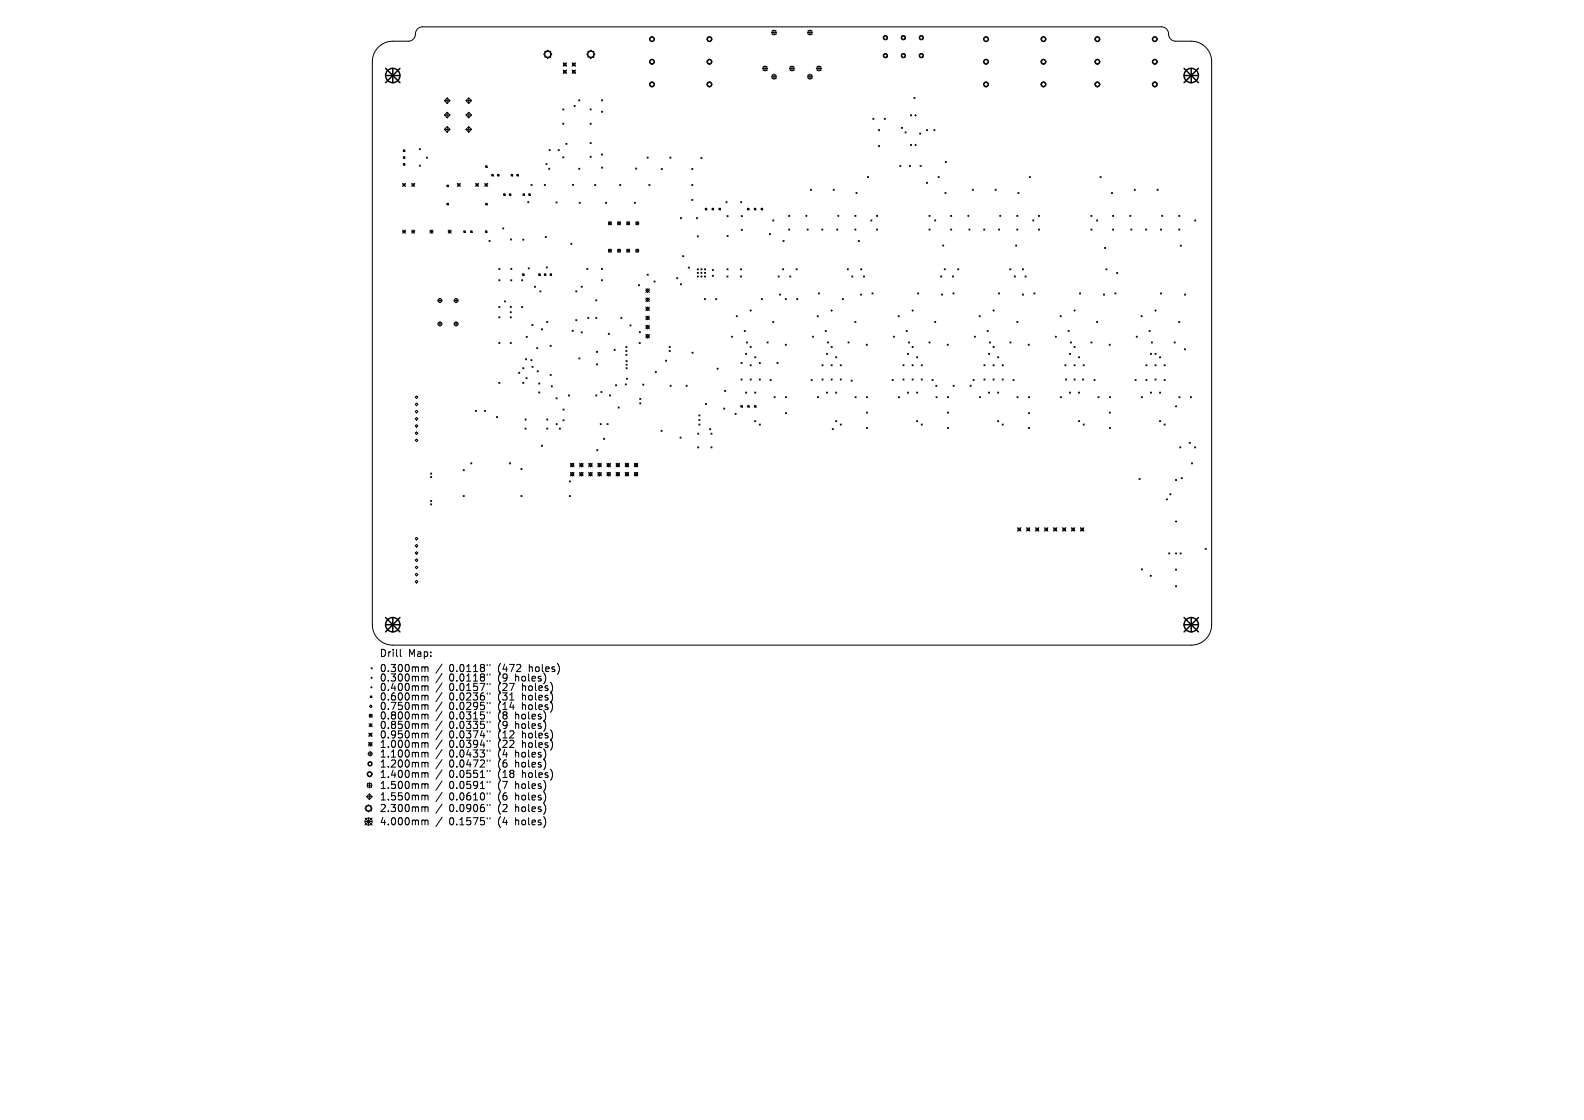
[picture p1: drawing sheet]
<svg xmlns="http://www.w3.org/2000/svg" width="297mm" height="210mm" viewBox="0 0 297 210" stroke-linecap="round" stroke-linejoin="round" font-family="sans-serif">
<defs><g id="words">
<g font-size="1.9">
<text x="71.1" y="123.4">Drill</text>
<text x="76.5" y="123.4">Map:</text>
<text x="71.1" y="126.2">0.300mm</text>
<text x="71.1" y="128">0.300mm</text>
<text x="71.1" y="129.7">0.400mm</text>
<text x="71.1" y="131.5">0.600mm</text>
<text x="84.2" y="126.2">0.0118&quot;</text>
<text x="84.2" y="128">0.0118&quot;</text>
<text x="84.2" y="129.7">0.0157&quot;</text>
<text x="84.2" y="131.5">0.0236&quot;</text>
<text x="93.5" y="126.2">(472</text>
<text x="93.5" y="128">(9</text>
<text x="93.5" y="129.7">(27</text>
<text x="93.5" y="131.5">(31</text>
<text x="96.8" y="128">holes)</text>
<text x="98.1" y="129.7">holes)</text>
<text x="98.1" y="131.5">holes)</text>
<text x="99.4" y="126.2">holes)</text>
<text x="71.1" y="133.3">0.750mm</text>
<text x="71.1" y="135.1">0.800mm</text>
<text x="71.1" y="136.9">0.850mm</text>
<text x="84.2" y="133.3">0.0295&quot;</text>
<text x="84.2" y="135.1">0.0315&quot;</text>
<text x="84.2" y="136.9">0.0335&quot;</text>
<text x="93.5" y="133.3">(14</text>
<text x="93.5" y="135.1">(8</text>
<text x="93.5" y="136.9">(9</text>
<text x="96.8" y="135.1">holes)</text>
<text x="96.8" y="136.9">holes)</text>
<text x="98.1" y="133.3">holes)</text>
<text x="71.1" y="138.6">0.950mm</text>
<text x="71.1" y="140.4">1.000mm</text>
<text x="71.1" y="142.2">1.100mm</text>
<text x="84.2" y="138.6">0.0374&quot;</text>
<text x="84.2" y="140.4">0.0394&quot;</text>
<text x="84.2" y="142.2">0.0433&quot;</text>
<text x="93.5" y="138.6">(12</text>
<text x="93.5" y="140.4">(22</text>
<text x="93.5" y="142.2">(4</text>
<text x="96.8" y="142.2">holes)</text>
<text x="98.1" y="138.6">holes)</text>
<text x="98.1" y="140.4">holes)</text>
<text x="71.1" y="144.1">1.200mm</text>
<text x="71.1" y="146">1.400mm</text>
<text x="71.1" y="148.1">1.500mm</text>
<text x="84.2" y="144.1">0.0472&quot;</text>
<text x="84.2" y="146">0.0551&quot;</text>
<text x="84.2" y="148.1">0.0591&quot;</text>
<text x="93.5" y="144.1">(6</text>
<text x="93.5" y="146">(18</text>
<text x="93.5" y="148.1">(7</text>
<text x="96.8" y="144.1">holes)</text>
<text x="96.8" y="148.1">holes)</text>
<text x="98.1" y="146">holes)</text>
<text x="71.1" y="150.3">1.550mm</text>
<text x="71.1" y="152.4">2.300mm</text>
<text x="71.1" y="154.9">4.000mm</text>
<text x="84.2" y="150.3">0.0610&quot;</text>
<text x="84.2" y="152.4">0.0906&quot;</text>
<text x="84.2" y="154.9">0.1575&quot;</text>
<text x="93.5" y="150.3">(6</text>
<text x="93.5" y="152.4">(2</text>
<text x="93.5" y="154.9">(4</text>
<text x="96.8" y="150.3">holes)</text>
<text x="96.8" y="152.4">holes)</text>
<text x="96.8" y="154.9">holes)</text>
</g>
</g></defs>
<g fill="none" stroke="#000" stroke-width=".19">
<path d="M70.9 8.8a3.8 3.8 0 0 1 2.7-1.1h2.9a1.48 1.48 0 0 0 1.4-1.7l.5-.7 .8-.3h138.6a1.47 1.47 0 0 1 1.4 1.7l.3 .6 .6 .4h3.3a3.8 3.8 0 0 1 3.8 3.9v105.5a3.8 3.8 0 0 1-3.8 3.9h-149.8a3.8 3.8 0 0 1-3.8-3.9v-105.5a3.8 3.8 0 0 1 1.1-2.8zM83.3 18.9l.5-.5 .6 .5-.6 .5zM83.3 18.9h1.1M83.8 18.4v1M87.4 18.9l.5-.5 .5 .5-.5 .5zM87.4 18.9h1M87.9 18.4v1M102.2 9.6h1.1v1.1h-1.1zM102.7 9.4l.8 .8-.8 .7-.8-.7zM105.6 11.8l.6 .6M105.6 13.1l.6 .7M105.7 11.9h.4v.4h-.4z"/>
<path d="M105.7 13.2h.4v.5h-.4zM106.2 11.8l-.6 .6M106.2 13.1l-.6 .7M107.3 11.8l.6 .6M107.3 13.1l.6 .7M107.4 11.9h.4v.4h-.4zM107.4 13.2h.4v.5h-.4zM107.7 19.8l.2 .2M107.9 19.8l-.2 .2M107.9 11.8l-.6 .6M107.9 13.1l-.6 .7M108.5 18.7l.2 .2"/>
<path d="M108.7 18.7l-.2 .2M110 10.2l.8-.8 .8 .8-.8 .7zM110.2 9.6h1.1v1.1h-1.1zM112.8 18.7l.2 .2M113 18.7l-.2 .2M122.2 6.9l.5 .4-.5 .5-.4-.5zM122.2 11.1l.5 .5-.5 .5-.4-.5zM122.2 15.4l.5 .4-.5 .5-.4-.5zM133 6.9l.5 .4-.5 .5-.4-.5zM133 11.1l.5 .5-.5 .5-.4-.5zM133 15.4l.5 .4-.5 .5-.4-.5zM142.9 12.8h1.1"/>
<path d="M143.1 12.5h.7v.7h-.7zM143.5 12.3v1M144.6 6.1h1M144.6 14.4h1M144.8 5.7h.7v.8h-.7zM144.8 14h.7v.7h-.7zM145.1 5.6v1M145.1 13.9v1M148 12.8h1M148.1 12.5h.8v.7h-.8zM148.5 12.3v1M151.4 6.1h1"/>
<path d="M151.4 14.4h1M151.5 5.7h.7v.8h-.7zM151.5 14h.7v.7h-.7zM151.9 5.6v1M151.9 13.9v1M153 12.8h1.1M153.2 12.5h.7v.7h-.7zM153.6 12.3v1M165.7 6.8h.6v.6h-.6zM165.7 10.1h.6v.6h-.6zM169.1 6.8h.6v.6h-.6zM169.1 10.1h.6v.6h-.6z"/>
<path d="M171.4 18.3l.2 .2M171.6 18.3l-.2 .2M172.5 6.8h.5v.6h-.5zM172.5 10.1h.5v.6h-.5zM184.4 7.3l.5-.4 .4 .4-.4 .5zM184.4 11.6l.5-.5 .4 .5-.4 .5zM184.4 15.8l.5-.4 .4 .4-.4 .5zM195.2 7.3l.5-.4 .4 .4-.4 .5zM195.2 11.6l.5-.5 .4 .5-.4 .5zM195.2 15.8l.5-.4 .4 .4-.4 .5zM205.3 7.3l.5-.4 .4 .4-.4 .5zM205.3 11.6l.5-.5 .4 .5-.4 .5z"/>
<path d="M205.3 15.8l.5-.4 .4 .4-.4 .5zM216.1 7.3l.4-.4 .5 .4-.5 .5zM216.1 11.6l.4-.5 .5 .5-.5 .5zM216.1 15.8l.4-.4 .5 .4-.5 .5zM75.5 34.4l.6 .6M75.5 34.7h.6M75.6 28.1h.3v.3h-.3zM75.6 29.4h.3v.3h-.3zM75.6 30.7h.3v.3h-.3zM75.8 34.4v.6M76.1 34.4l-.6 .6M77.2 34.7h.6"/>
<path d="M77.2 34.4l.6 .6M77.5 34.4v.6M77.8 34.4l-.6 .6M78.6 27.9l.2 .2M78.6 31l.2 .2M78.8 27.9l-.2 .2M78.8 31l-.2 .2M79.9 29.5l.3 .2M80.2 29.5l-.3 .2M83.3 21.6l.5-.6 .6 .6-.6 .5zM83.3 21.6h1.1M83.3 24.3h1.1"/>
<path d="M83.8 34.7h.3v.3h-.3zM83.8 38.1h.3v.3h-.3zM83.8 23.7l.6 .6-.6 .5-.5-.5zM83.8 21v1.1M83.8 23.7v1.1M85.7 34.7h.6M85.7 34.4l.6 .6M86 34.4v.6M86.3 34.4l-.6 .6M87.4 21.6l.5-.6 .5 .6-.5 .5zM87.4 21.6h1M87.4 24.3h1"/>
<path d="M87.9 23.7l.5 .6-.5 .5-.5-.5zM87.9 21v1.1M87.9 23.7v1.1M89.2 34.7h.5M89.2 34.4l.5 .6M89.5 34.4v.6M89.7 34.4l-.5 .6M90.9 34.4l.5 .6M90.9 34.7h.5M91.1 31.1h.2v.3h-.2zM91.1 38.1h.2v.3h-.2zM91.2 34.4v.6"/>
<path d="M91.4 34.4l-.5 .6M92.2 32.7h.3v.3h-.3zM93.3 32.7h.3v.3h-.3zM94.4 36.3h.3v.3h-.3zM95.5 36.3h.3v.3h-.3zM95.8 32.7h.3v.3h-.3zM96.9 32.7h.3v.3h-.3zM98.1 36.3h.2v.3h-.2zM99 37.8l.2 .2M99.1 36.3h.3v.3h-.3zM99.2 37.8l-.2 .2M99.6 34.6l.2 .2"/>
<path d="M99.8 34.6l-.2 .2M102.1 34.6l.2 .2M102.3 34.6l-.2 .2M102.4 30.7l.2 .2M102.6 30.7l-.2 .2M102.9 31.5l.2 .2M103 28l.2 .2M103.1 31.5l-.2 .2M103.2 28l-.2 .2M104.2 37.9l.2 .2M104.4 37.9l-.2 .2M104.7 28l.2 .2"/>
<path d="M104.9 28l-.2 .2M105.5 20.4l.2 .2M105.5 23.1l.2 .2M105.5 29.4l.2 .2M105.7 20.4l-.2 .2M105.7 23.1l-.2 .2M105.7 29.4l-.2 .2M106.1 26.9l.2 .2M106.3 26.9l-.2 .2M107.3 34.6l.2 .2M107.5 34.6l-.2 .2M108.5 31.5l.2 .2"/>
<path d="M108.6 37.9l.2 .2M108.7 31.5l-.2 .2M108.8 37.9l-.2 .2M110.6 20.4l.3 .2M110.6 23.1l.3 .2M110.6 26.7l.3 .2M110.6 29.3l.3 .2M110.9 20.4l-.3 .2M110.9 23.1l-.3 .2M110.9 26.7l-.3 .2M110.9 29.3l-.3 .2M111.5 34.6l.2 .2"/>
<path d="M111.7 34.6l-.2 .2M112.8 20.9l.2 .2M112.8 28.9l.2 .2M112.8 31.3l.2 .2M113 20.9l-.2 .2M113 28.9l-.2 .2M113 31.3l-.2 .2M113.5 37.9l.2 .2M113.7 37.9l-.2 .2M116.2 34.6l.2 .2M116.4 34.6l-.2 .2M118.9 37.9l.2 .2"/>
<path d="M119.1 37.9l-.2 .2M119.2 31.5l.2 .2M119.4 31.5l-.2 .2M121.3 29.5l.2 .2M121.5 29.5l-.2 .2M121.7 34.6l.2 .2M121.9 34.6l-.2 .2M124 31.6l.2 .2M124.2 31.6l-.2 .2M125.6 29.5l.2 .2M125.8 29.5l-.2 .2M129.7 31.6l.2 .2"/>
<path d="M129.7 34.6l.2 .2M129.7 37.4l.2 .2M129.9 31.6l-.2 .2M129.9 34.6l-.2 .2M129.9 37.4l-.2 .2M131.4 29.5l.2 .2M131.6 29.5l-.2 .2M132.2 39.1h.3v.2h-.3zM133.5 39.1h.3v.2h-.3zM134.8 39.1h.3v.2h-.3zM136.1 37.8l.2 .2M136.3 37.8l-.2 .2"/>
<path d="M138.9 37.8l.2 .2M139.1 37.8l-.2 .2M140.1 39.1h.3v.2h-.3zM141.4 39.1h.3v.2h-.3zM142.7 39.1h.3v.2h-.3zM151.9 35.5l.2 .2M152.1 35.5l-.2 .2M156.2 35.5l.2 .2M156.4 35.5l-.2 .2M160.5 36.1l.2 .2M160.7 36.1l-.2 .2M162.6 33.1l.2 .2"/>
<path d="M162.8 33.1l-.2 .2M163.7 22.2l.2 .2M163.9 22.2l-.2 .2M164.7 24.3l.2 .2M164.7 27.3l.2 .2M164.9 24.3l-.2 .2M164.9 27.3l-.2 .2M165.8 22.2l.2 .2M166 22.2l-.2 .2M168.7 31l.2 .2M168.9 31l-.2 .2M169 23.9l.2 .2"/>
<path d="M169.2 23.9l-.2 .2M169.7 24.7l.2 .2M169.9 24.7l-.2 .2M170.5 31l.2 .2M170.7 31l-.2 .2M170.7 21.5l.2 .2M170.7 27.1l.2 .2M170.9 21.5l-.2 .2M170.9 27.1l-.2 .2M171.5 21.6h.3M171.5 27.2h.3M171.7 21.5v.3"/>
<path d="M171.7 27v.3M172.4 24.9l.2 .2M172.5 31l.2 .2M172.6 24.9l-.2 .2M172.7 31l-.2 .2M173.7 34.2l.2 .2M173.7 24.3l.2 .2M173.9 34.2l-.2 .2M173.9 24.3l-.2 .2M175.1 24.3l.2 .2M175.3 24.3l-.2 .2M175.9 33.1l.2 .2"/>
<path d="M176.1 33.1l-.2 .2M177.2 36.1l.2 .2M177.2 30.3l.2 .2M177.4 36.1l-.2 .2M177.4 30.3l-.2 .2M182.3 35.5l.2 .2M182.5 35.5l-.2 .2M186.6 35.5l.2 .2M186.8 35.5l-.2 .2M190.9 36.1l.2 .2M191.1 36.1l-.2 .2M193 33.1l.2 .2"/>
<path d="M193.2 33.1l-.2 .2M206.3 33.1l.2 .2M206.5 33.1l-.2 .2M208.4 36.1l.2 .2M208.6 36.1l-.2 .2M212.7 35.5l.2 .2M212.9 35.5l-.2 .2M217 35.5l.2 .2M217.2 35.5l-.2 .2M75.5 43.1l.6 .6M75.5 43.4h.6M75.8 43.1v.6"/>
<path d="M76.1 43.1l-.6 .6M77.2 43.4h.6M77.2 43.1l.6 .6M77.5 43.1v.6M77.8 43.1l-.6 .6M80.6 43.4h.6M80.6 43.1l.6 .6M80.9 43.1v.6M81.2 43.1l-.6 .6M82.1 56.4h.8M82.5 56v.7M84 43.4h.6"/>
<path d="M84 43.1l.6 .6M84.3 43.1v.6M84.6 43.1l-.6 .6M85.2 56.4h.7M85.5 56v.7M87 43.3h.2v.3h-.2zM88.2 43.3h.3v.3h-.3zM91 43.3h.3v.3h-.3zM91.7 45.1l.2 .2M91.9 45.1l-.2 .2M93.5 50.3l.2 .2M93.5 52.5l.2 .2"/>
<path d="M93.5 57.5l.2 .2M93.5 59.4l.2 .2M93.7 50.3l-.2 .2M93.7 52.5l-.2 .2M93.7 57.5l-.2 .2M93.7 59.4l-.2 .2M94.3 42.7l.2 .2M94.5 42.7l-.2 .2M94.6 56.5h.2M94.7 56.4v.2M95.7 57.5l.2 .2M95.7 58.4l.2 .2"/>
<path d="M95.7 59.4l.2 .2M95.7 44.8l.2 .2M95.8 50.3l.2 .2M95.8 52.5l.2 .2M95.9 57.5l-.2 .2M95.9 58.4l-.2 .2M95.9 59.4l-.2 .2M95.9 44.8l-.2 .2M96 50.3l-.2 .2M96 52.5l-.2 .2M97.8 52.5l.2 .2M97.8 57.5l.2 .2"/>
<path d="M98 51.3h.3v.3h-.3zM98 52.5l-.2 .2M98 57.5l-.2 .2M98 44.8l.2 .2M98.2 44.8l-.2 .2M99 50.2l.2 .2M99.2 50.2l-.2 .2M100.2 53.7l.2 .2M100.4 53.7l-.2 .2M101 51.3h.3v.3h-.3zM101.2 54.5l.2 .2M101.4 54.5l-.2 .2"/>
<path d="M102.1 51.3h.3v.3h-.3zM102.2 44.3l.2 .2M102.4 50l.2 .3M102.4 44.3l-.2 .2M102.6 50l-.2 .3M103.1 51.3h.3v.3h-.3zM107 45.6l.2 .2M107.2 45.6l-.2 .2M108 54.5l.2 .2M108 59.9l.2 .2M108.2 59.9l-.2 .2M108.2 54.5l-.2 .2"/>
<path d="M109 53.7l.2 .2M109.2 53.7l-.2 .2M110 50.3l.2 .2M110.2 59.5l.2 .2M110.2 50.3l-.2 .2M110.4 59.5l-.2 .2M111.7 56.2l.2 .2M111.7 59.5l.2 .2M111.9 59.5l-.2 .2M111.9 56.2l-.2 .2M112.8 50.3l.2 .2M112.8 52.5l.2 .2"/>
<path d="M113 52.5l-.2 .2M113 50.3l-.2 .2M114.1 41.6l.5 .5M114.1 46.7l.5 .6M114.6 41.6l-.5 .5M114.6 46.7l-.5 .6M115.8 41.6l.5 .5M115.8 46.7l.5 .6M116.3 41.6l-.5 .5M116.3 46.7l-.5 .6M116.4 59.5l.2 .2M116.6 59.5l-.2 .2"/>
<path d="M117.5 41.6l.6 .5M117.5 46.7l.6 .6M118.1 41.6l-.6 .5M118.1 46.7l-.6 .6M119.2 41.6l.6 .5M119.2 46.7l.6 .6M119.7 53.4l.2 .2M119.8 41.6l-.6 .5M119.8 46.7l-.6 .6M119.9 53.4l-.2 .2M121.1 54.5l.3-.4 .4 .4-.4 .3zM121.1 54.1l.7 .7"/>
<path d="M121.1 55.9l.7 .6M121.1 57.6l.7 .6M121.1 59.3l.7 .6M121.3 51.4l.2 .2M121.4 55.9l.4 .3-.4 .3-.3-.3zM121.4 57.6l.4 .3-.4 .3-.3-.3zM121.4 59.3l.4 .3-.4 .3-.3-.3zM121.5 51.4l-.2 .2M121.8 54.1l-.7 .7M121.8 55.9l-.7 .6M121.8 57.6l-.7 .6M121.8 59.3l-.7 .6"/>
<path d="M122.6 52.7l.2 .2M122.8 52.7l-.2 .2M126.9 52.1l.2 .2M127.1 52.1l-.2 .2M127.6 40.8l.2 .2M127.6 53.2l.2 .2M127.8 40.8l-.2 .2M127.8 53.2l-.2 .2M128 47.9l.2 .3M128.2 47.9l-.2 .3M129 50.2h.3M129.2 50.1v.2"/>
<path d="M130.6 40.8l.2 .2M130.7 44.2l.2 .2M130.8 40.8l-.2 .2M130.9 44.2l-.2 .2M132.1 56l.2 .2M132.3 56l-.2 .2M133.6 50.5l.2 .2M133.6 51.6l.2 .2M133.8 50.5l-.2 .2M133.8 51.6l-.2 .2M134.2 56l.2 .2M134.4 56l-.2 .2"/>
<path d="M136.3 50.4l.2 .2M136.3 51.7l.2 .2M136.3 40.4l.2 .2M136.3 44.2l.2 .2M136.5 51.7l-.2 .2M136.5 50.4l-.2 .2M136.5 40.4l-.2 .2M136.5 44.2l-.2 .2M138 59.2l.2 .2M138.2 59.2l-.2 .2M138.8 51.7l.2 .2M138.8 50.4l.2 .2"/>
<path d="M139 40.4l.2 .2M139 43l.2 .2M139 51.7l-.2 .2M139 50.4l-.2 .2M139.2 40.4l-.2 .2M139.2 43l-.2 .2M140.6 58.2h.3M140.8 58.1v.3M142.8 56l.2 .2M143 56l-.2 .2M144.2 43.8l.3 .2M144.5 43.8l-.3 .2"/>
<path d="M144.9 41.2l.2 .2M145.1 41.2l-.2 .2M145.9 51.7l.2 .2M146.1 51.7l-.2 .2M146.2 55.1l.2 .2M146.4 55.1l-.2 .2M146.7 50.4l.2 .2M146.8 45.1l.2 .2M146.9 50.4l-.2 .2M147 45.1l-.2 .2M147.2 56l.2 .2M147.4 56l-.2 .2"/>
<path d="M147.9 40.4l.2 .2M147.9 42.9l.2 .2M148.1 40.4l-.2 .2M148.1 42.9l-.2 .2M148.1 51.7l.2 .2M148.3 51.7l-.2 .2M149.3 50.4l.2 .2M149.4 56l.2 .2M149.5 50.4l-.2 .2M149.6 56l-.2 .2M151.1 40.5h.2M151.2 40.3v.3"/>
<path d="M151.3 42.9l.2 .2M151.5 42.9l-.2 .2M153.2 59.2l.2 .2M153.4 59.2l-.2 .2M153.4 54.9l.2 .2M153.6 54.9l-.2 .2M154.1 42.9l.2 .2M154.3 42.9l-.2 .2M155.8 58.2h.3M155.9 58.1v.3M156.9 42.9l.2 .2M157 40.5h.3"/>
<path d="M157.1 42.9l-.2 .2M157.2 40.3v.3M157.9 56l.2 .2M158.1 56l-.2 .2M158.9 50.4l.2 .2M159.1 50.4l-.2 .2M159.7 51.7l.2 .2M159.9 51.7l-.2 .2M160.3 40.4l.2 .2M160.3 42.9l.2 .2M160.5 42.9l-.2 .2M160.5 40.4l-.2 .2"/>
<path d="M160.9 45.1l.2 .2M161.1 45.1l-.2 .2M161.4 55.1l.2 .2M161.4 50.4l.2 .2M161.6 55.1l-.2 .2M161.6 50.4l-.2 .2M161.9 51.7l.2 .2M162.1 51.7l-.2 .2M163.3 41.2l.2 .2M163.5 41.2l-.2 .2M163.5 54.9l.2 .2M163.7 54.9l-.2 .2"/>
<path d="M164.3 40.4l.3 .2M164.3 42.9l.3 .2M164.6 40.4l-.3 .2M164.6 42.9l-.3 .2M168.4 59.2l.2 .2M168.6 59.2l-.2 .2M171 58.2h.3M171.1 58.1v.3M172 54.9l.2 .2M172.2 54.9l-.2 .2M174.2 40.4l.2 .2M174.2 42.9l.2 .2"/>
<path d="M174.4 40.4l-.2 .2M174.4 42.9l-.2 .2M175.3 41.2l.2 .2M175.5 41.2l-.2 .2M176.4 51.7l.2 .2M176.5 55.1l.2 .2M176.6 51.7l-.2 .2M176.7 55.1l-.2 .2M176.8 45.9l.2 .2M177 45.9l-.2 .2M177 50.4l.2 .2M177.2 50.4l-.2 .2"/>
<path d="M178.2 40.4l.2 .2M178.2 42.9l.2 .2M178.4 40.4l-.2 .2M178.4 42.9l-.2 .2M178.6 51.7l.2 .2M178.7 54.9l.2 .2M178.8 51.7l-.2 .2M178.9 54.9l-.2 .2M179.6 50.4l.2 .2M179.8 50.4l-.2 .2M181.4 40.5h.3M181.6 40.3v.3"/>
<path d="M181.7 42.9l.2 .2M181.9 42.9l-.2 .2M183.6 59.2l.2 .2M183.8 59.2l-.2 .2M184.4 42.9l.3 .2M184.7 42.9l-.3 .2M186.2 58.2h.2M186.3 58.1v.3M187.2 42.9l.2 .2M187.2 54.9l.2 .2M187.4 40.5h.3M187.4 42.9l-.2 .2"/>
<path d="M187.4 54.9l-.2 .2M187.5 40.3v.3M189.3 50.4l.2 .2M189.5 50.4l-.2 .2M190.2 51.7l.2 .2M190.4 51.7l-.2 .2M190.4 45.9l.2 .2M190.6 45.9l-.2 .2M190.6 40.4l.3 .2M190.6 42.9l.3 .2M190.9 42.9l-.3 .2M190.9 40.4l-.3 .2"/>
<path d="M191.7 50.4l.2 .2M191.7 55.1l.2 .2M191.9 50.4l-.2 .2M191.9 55.1l-.2 .2M192.2 51.7l.2 .2M192.4 51.7l-.2 .2M193.6 41.2l.2 .2M193.8 41.2l-.2 .2M193.9 54.9l.2 .2M194.1 54.9l-.2 .2M194.7 40.4l.2 .2M194.7 42.9l.2 .2"/>
<path d="M194.9 42.9l-.2 .2M194.9 40.4l-.2 .2M198.8 59.2l.2 .2M199 59.2l-.2 .2M201.3 58.2h.3M201.5 58.1v.3M202.4 54.9l.2 .2M202.6 54.9l-.2 .2M204.5 40.4l.3 .2M204.5 42.9l.3 .2M204.8 40.4l-.3 .2M204.8 42.9l-.3 .2"/>
<path d="M205.6 41.2l.2 .2M205.8 41.2l-.2 .2M206.9 55.1l.2 .2M207.1 55.1l-.2 .2M207.1 46.4l.2 .2M207.3 46.4l-.2 .2M207.4 50.4l.2 .2M207.6 50.4l-.2 .2M208.6 40.4l.2 .2M208.6 42.9l.2 .2M208.8 40.4l-.2 .2M208.8 42.9l-.2 .2"/>
<path d="M209 54.9l.2 .2M209.2 54.9l-.2 .2M209.4 51.1l.2 .2M209.6 51.1l-.2 .2M211.8 40.5h.3M211.9 40.3v.3M212 42.9l.2 .2M212.2 42.9l-.2 .2M214 59.2l.2 .2M214.2 59.2l-.2 .2M214.8 42.9l.2 .2M215 42.9l-.2 .2"/>
<path d="M216.5 58.2h.3M216.7 58.1v.3M217.6 42.9l.2 .2M217.6 54.9l.2 .2M217.8 40.5h.2M217.8 42.9l-.2 .2M217.8 54.9l-.2 .2M217.9 40.3v.3M221 40.4l.2 .2M221 42.9l.2 .2M221.2 42.9l-.2 .2M221.2 40.4l-.2 .2"/>
<path d="M221.3 46l.2 .2M221.5 46l-.2 .2M222.1 55.1l.2 .2M222.3 55.1l-.2 .2M224 41.2l.2 .2M224.2 41.2l-.2 .2M77.9 74.5l.2-.3 .3 .3-.3 .2zM77.9 75.8l.2-.2 .3 .2-.3 .3zM77.9 77.2l.2-.3 .3 .3-.3 .2zM77.9 78.5l.2-.2 .3 .2-.3 .3zM77.9 79.9l.2-.3 .3 .3-.3 .2zM82.1 60.7h.8"/>
<path d="M82.5 60.4v.7M85.2 60.7h.7M85.5 60.4v.7M89.1 76.9l.2 .2M89.3 76.9l-.2 .2M90.8 76.9l.2 .2M91 76.9l-.2 .2M93.1 78.1l.2 .2M93.3 78.1l-.2 .2M93.5 64.2l.2 .2M93.5 71.7l.2 .2M93.7 64.2l-.2 .2"/>
<path d="M93.7 71.7l-.2 .2M95.7 64.2l.2 .2M95.9 64.2l-.2 .2M97.2 69.8l.3 .2M97.5 69.8l-.3 .2M98 69l.2 .2M98 71.7l.2 .2M98.2 69l-.2 .2M98.2 71.7l-.2 .2M98.5 78.6l.2 .2M98.5 67.3l.2 .2M98.6 70.8l.2 .2"/>
<path d="M98.7 63.1l.2 .2M98.7 78.6l-.2 .2M98.7 67.3l-.2 .2M98.8 70.8l-.2 .2M98.9 63.1l-.2 .2M99.5 67.4l.2 .2M99.7 60.8l.2 .2M99.7 67.4l-.2 .2M99.7 68.7l.3 .2M99.9 60.8l-.2 .2M100 68.7l-.3 .2M100.6 65.2l.2 .2"/>
<path d="M100.7 69.5l.2 .2M100.8 65.2l-.2 .2M100.9 69.5l-.2 .2M101 73.5l.2 .2M101 71.8l.2 .2M101.2 73.5l-.2 .2M101.2 71.8l-.2 .2M101.5 61.6l.2 .3M101.7 61.6l-.2 .3M102.5 60.3l.2 .2M102.5 78.6l.2 .2M102.7 60.3l-.2 .2"/>
<path d="M102.7 78.6l-.2 .2M103.1 64.7l.3 .2M103.1 70.2l.3 .2M103.4 64.7l-.3 .2M103.4 70.2l-.3 .2M103.4 72.3l.2 .2M103.6 72.3l-.2 .2M104.3 74.6l.2 .2M104.3 79.5h.2M104.4 79.4v.3M104.5 74.6l-.2 .2M105.6 78.7l.2 .2"/>
<path d="M105.6 76.7l.2 .2M105.8 78.7l-.2 .2M105.8 76.7l-.2 .2M106.6 74.1l.2 .2M106.8 74.1l-.2 .2M107.3 61.9l.2 .2M107.5 61.9l-.2 .2M108.5 67.1l.2 .2M108.7 67.1l-.2 .2M109 62.2l.2 .2M109.2 62.2l-.2 .2M111.7 74.1l.2 .2"/>
<path d="M111.8 65.9l.2 .2M111.8 68.2l.2 .2M111.9 74.1l-.2 .2M112 65.9l-.2 .2M112 68.2l-.2 .2M112.5 79.4l.2 .2M112.7 73.4l.2 .2M112.7 79.4l-.2 .2M112.9 73.4l-.2 .2M113.8 79.4l.2 .2M114 79.4l-.2 .2M114.1 62.5l.2 .2"/>
<path d="M114.3 62.5l-.2 .2M114.3 74.1l.2 .2M114.5 74.1l-.2 .2M115.2 65.5l.2 .2M115.4 65.5l-.2 .2M115.4 72.1l.2 .3M115.6 72.1l-.2 .3M115.9 76.3l.2 .2M116.1 76.3l-.2 .2M117.2 72l.2 .2M117.3 65l.2 .2M117.3 65.7l.2 .2"/>
<path d="M117.3 66.4l.2 .2M117.4 67.6l.2 .2M117.4 68.3l.2 .2M117.4 69l.2 .2M117.4 72l-.2 .2M117.5 70.9l.2 .2M117.5 65l-.2 .2M117.5 65.7l-.2 .2M117.5 66.4l-.2 .2M117.6 67.6l-.2 .2M117.6 68.3l-.2 .2M117.6 69l-.2 .2"/>
<path d="M117.7 70.9l-.2 .2M118.1 60.9l.2 .2M118.3 60.9l-.2 .2M119.8 64.2l.3 .2M119.9 62.2l.2 .2M120 74.7l.2 .2M120 75.5l.2 .2M120.1 64.2l-.3 .2M120.1 62.2l-.2 .2M120.2 74.7l-.2 .2M120.2 75.5l-.2 .2M120.5 72l.2 .2"/>
<path d="M120.7 72l-.2 .2M121.1 61l.7 .7M121.1 62.7l.7 .7M121.4 61l.4 .3-.4 .4-.3-.4zM121.4 62.7l.4 .3-.4 .4-.3-.4zM121.8 62.7l-.7 .7M121.8 61l-.7 .7M122.9 69.7l.2 .2M123.1 69.7l-.2 .2M124.8 67.5l.2 .2M125 67.5l-.2 .2M125.5 65l.2 .2"/>
<path d="M125.5 65.7l.2 .2M125.6 72.2l.2 .2M125.7 65l-.2 .2M125.7 65.7l-.2 .2M125.8 72.2l-.2 .2M128.6 72.2l.2 .2M128.8 72.2l-.2 .2M129.7 66l.3 .2M130 66l-.3 .2M131 77.8l.2 .2M131 78.7l.2 .2M131 79.5l.2 .2"/>
<path d="M131.2 77.8l-.2 .2M131.2 78.7l-.2 .2M131.2 79.5l-.2 .2M132.3 75.7l.2 .2M132.5 75.7l-.2 .2M134.5 69l.2 .2M134.7 69l-.2 .2M135.7 76.5l.2 .2M135.9 73.2l.2 .2M135.9 76.5l-.2 .2M136.1 73.2l-.2 .2M137.1 63.1h.3"/>
<path d="M137.3 63v.3M137.8 77.5l.2 .2M138 77.5l-.2 .2M138.9 76h.3v.3h-.3zM138.9 68l.2 .2M138.9 71.1l.2 .2M139.1 68l-.2 .2M139.1 71.1l-.2 .2M139.5 62l.2 .2M139.7 62l-.2 .2M139.8 66.3l.2 .2M139.8 73.5l.2 .2"/>
<path d="M140 64.1l.2 .2M140 66.3l-.2 .2M140 73.5l-.2 .2M140.2 64.1l-.2 .2M140.2 76h.3v.3h-.3zM140.7 65l.2 .2M140.7 68.4l.2 .2M140.7 71.1l.2 .2M140.9 68.4l-.2 .2M140.9 65l-.2 .2M140.9 71.1l-.2 .2M141.5 76h.3v.3h-.3z"/>
<path d="M141.5 66.9l.2 .2M141.5 73.5l.2 .2M141.5 78.9l.2 .2M141.7 66.9l-.2 .2M141.7 73.5l-.2 .2M141.7 78.9l-.2 .2M142.4 68l.2 .2M142.4 71.1l.2 .2M142.4 79.5l.2 .2M142.6 71.1l-.2 .2M142.6 68l-.2 .2M142.6 79.5l-.2 .2"/>
<path d="M143.8 64.1l.2 .2M144 64.1l-.2 .2M144.4 71.2l.2 .2M144.6 71.2l-.2 .2M144.9 60.3l.2 .2M145.1 60.3l-.2 .2M145.1 74.4l.2 .2M145.3 74.4l-.2 .2M145.7 68l.2 .2M145.9 68l-.2 .2M147.2 64.5l.2 .2M147.3 74.4l.2 .2"/>
<path d="M147.3 77.4l.2 .2M147.4 64.5l-.2 .2M147.5 74.4l-.2 .2M147.5 77.4l-.2 .2M152.1 71.2l.2 .2M152.3 71.2l-.2 .2M152.3 63.1h.3M152.4 63v.3M153.3 74.4l.2 .2M153.5 74.4l-.2 .2M154.1 68.4l.2 .2M154.1 71.1l.2 .2"/>
<path d="M154.3 68.4l-.2 .2M154.3 71.1l-.2 .2M154.7 62l.2 .2M154.9 62l-.2 .2M155 73.5l.2 .2M155 66.3l.2 .2M155.2 64.1l.2 .2M155.2 66.3l-.2 .2M155.2 73.5l-.2 .2M155.4 64.1l-.2 .2M155.8 65l.2 .2M155.8 68.4l.2 .2"/>
<path d="M155.8 71.1l.2 .2M156 65l-.2 .2M156 68.4l-.2 .2M156 71.1l-.2 .2M156.7 66.9l.2 .2M156.7 73.5l.2 .2M156.7 78.9l.2 .2M156.9 66.9l-.2 .2M156.9 73.5l-.2 .2M156.9 78.9l-.2 .2M157.5 68.4l.2 .2M157.5 71.1l.2 .2"/>
<path d="M157.5 79.5l.2 .2M157.7 68.4l-.2 .2M157.7 71.1l-.2 .2M157.7 79.5l-.2 .2M159 64.1l.2 .2M159.2 64.1l-.2 .2M159.6 71.3l.2 .2M159.8 71.3l-.2 .2M160.3 60.3l.2 .2M160.3 74.4l.2 .2M160.5 60.3l-.2 .2M160.5 74.4l-.2 .2"/>
<path d="M162.4 64.5l.2 .2M162.5 74.4l.2 .2M162.5 77.3l.2 .2M162.6 64.5l-.2 .2M162.7 74.4l-.2 .2M162.7 77.3l-.2 .2M167.3 71.2l.2 .2M167.5 71.2l-.2 .2M167.5 63.1h.3M167.6 63v.3M168.5 74.4l.2 .2M168.7 74.4l-.2 .2"/>
<path d="M169.3 68.4l.2 .2M169.3 71.1l.2 .2M169.5 68.4l-.2 .2M169.5 71.1l-.2 .2M169.9 62l.2 .2M170.1 62l-.2 .2M170.2 66.3l.2 .2M170.2 73.5l.2 .2M170.3 64.1l.2 .2M170.4 66.3l-.2 .2M170.4 73.5l-.2 .2M170.5 64.1l-.2 .2"/>
<path d="M171 65l.2 .2M171 68.4l.2 .2M171 71.1l.2 .2M171.2 65l-.2 .2M171.2 68.4l-.2 .2M171.2 71.1l-.2 .2M171.9 66.9l.2 .2M171.9 73.5l.2 .2M171.9 78.9l.2 .2M172.1 66.9l-.2 .2M172.1 73.5l-.2 .2M172.1 78.9l-.2 .2"/>
<path d="M172.7 68.4l.2 .2M172.7 71.1l.2 .2M172.7 79.5l.2 .2M172.9 68.4l-.2 .2M172.9 71.1l-.2 .2M172.9 79.5l-.2 .2M174.2 64.1l.2 .2M174.4 64.1l-.2 .2M174.8 71.2l.2 .2M175 71.2l-.2 .2M175.3 60.3l.2 .2M175.5 60.3l-.2 .2"/>
<path d="M175.5 72.2l.2 .2M175.5 74.4l.2 .2M175.7 72.2l-.2 .2M175.7 74.4l-.2 .2M177.6 64.5l.2 .2M177.6 74.4l.2 .2M177.6 77.3l.2 .2M177.8 64.5l-.2 .2M177.8 74.4l-.2 .2M177.8 77.3l-.2 .2M178.7 72.2l.2 .2M178.9 72.2l-.2 .2"/>
<path d="M181.9 72.2l.2 .2M182.1 72.2l-.2 .2M182.5 71.2l.2 .2M182.7 71.2l-.2 .2M182.7 63.1h.2M182.8 63v.3M183.6 74.4l.2 .2M183.8 74.4l-.2 .2M184.5 68.4l.2 .2M184.5 71.1l.2 .2M184.7 68.4l-.2 .2M184.7 71.1l-.2 .2"/>
<path d="M185.1 62l.2 .2M185.3 62l-.2 .2M185.3 66.3l.2 .2M185.3 73.5l.2 .2M185.5 64.1l.2 .2M185.5 66.3l-.2 .2M185.5 73.5l-.2 .2M185.7 64.1l-.2 .2M186.2 65l.2 .2M186.2 68.4l.2 .2M186.2 71.1l.2 .2M186.4 65l-.2 .2"/>
<path d="M186.4 68.4l-.2 .2M186.4 71.1l-.2 .2M187.1 66.9l.2 .2M187.1 73.5l.2 .2M187.1 78.9l.2 .2M187.3 66.9l-.2 .2M187.3 73.5l-.2 .2M187.3 78.9l-.2 .2M187.9 68.4l.2 .2M187.9 71.1l.2 .2M187.9 79.5l.2 .2M188.1 68.4l-.2 .2"/>
<path d="M188.1 71.1l-.2 .2M188.1 79.5l-.2 .2M189.4 64.1l.2 .2M189.6 64.1l-.2 .2M189.9 71.2l.2 .2M190.1 71.2l-.2 .2M190.6 60.3l.3 .2M190.7 74.4l.2 .2M190.9 60.3l-.3 .2M190.9 74.4l-.2 .2M192.8 64.5l.2 .2M192.8 74.4l.2 .2"/>
<path d="M192.8 77.4l.2 .2M193 64.5l-.2 .2M193 74.4l-.2 .2M193 77.4l-.2 .2M197.8 63.1h.3M198 63v.3M198.8 74.4l.2 .2M199 74.4l-.2 .2M199.7 68.4l.2 .2M199.8 71.1l.2 .2M199.9 68.4l-.2 .2M200 71.1l-.2 .2"/>
<path d="M200.3 62l.2 .2M200.5 62l-.2 .2M200.5 66.3l.2 .2M200.5 73.5l.2 .2M200.7 64.1l.2 .2M200.7 66.3l-.2 .2M200.7 73.5l-.2 .2M200.9 64.1l-.2 .2M201.4 65l.2 .2M201.4 68.4l.2 .2M201.4 71.1l.2 .2M201.6 65l-.2 .2"/>
<path d="M201.6 68.4l-.2 .2M201.6 71.1l-.2 .2M202.2 66.9l.2 .2M202.2 73.5l.2 .2M202.2 78.9l.2 .2M202.4 66.9l-.2 .2M202.4 73.5l-.2 .2M202.4 78.9l-.2 .2M203 71.1l.2 .2M203.1 68.4l.2 .2M203.1 79.5l.2 .2M203.2 71.1l-.2 .2"/>
<path d="M203.3 68.4l-.2 .2M203.3 79.5l-.2 .2M204.5 64.1l.3 .2M204.8 64.1l-.3 .2M205.1 71.2l.2 .2M205.3 71.2l-.2 .2M205.6 60.3l.2 .2M205.8 60.3l-.2 .2M205.9 74.4l.2 .2M206.1 74.4l-.2 .2M208 64.5l.2 .2M208 74.4l.2 .2"/>
<path d="M208 77.3l.2 .2M208.2 64.5l-.2 .2M208.2 74.4l-.2 .2M208.2 77.3l-.2 .2M212.8 71.2l.2 .2M213 71.2l-.2 .2M213 63.1h.3M213.2 63v.3M214 74.4l.2 .2M214.2 74.4l-.2 .2M214.9 68.4l.2 .2M214.9 71.2l.2 .2"/>
<path d="M215.1 68.4l-.2 .2M215.1 71.2l-.2 .2M215.5 62l.2 .2M215.7 62l-.2 .2M215.7 66.3l.2 .2M215.7 73.5l.2 .2M215.9 64.1l.2 .2M215.9 66.3l-.2 .2M215.9 73.5l-.2 .2M216.1 64.1l-.2 .2M216.6 66.3l.2 .2M216.6 68.4l.2 .2"/>
<path d="M216.6 71.1l.2 .2M216.8 66.3l-.2 .2M216.8 68.4l-.2 .2M216.8 71.1l-.2 .2M217.4 66.9l.2 .2M217.4 73.5l.2 .2M217.4 78.9l.2 .2M217.6 66.9l-.2 .2M217.6 73.5l-.2 .2M217.6 78.9l-.2 .2M218.3 68.4l.2 .2M218.3 71.2l.2 .2"/>
<path d="M218.3 79.5l.2 .2M218.5 68.4l-.2 .2M218.5 71.2l-.2 .2M218.5 79.5l-.2 .2M220.2 64.1l.2 .2M220.4 64.1l-.2 .2M220.4 76.2h.2M220.5 76.1v.2M221 60.3l.2 .2M221.1 74.4l.2 .2M221.2 60.3l-.2 .2M221.3 74.4l-.2 .2"/>
<path d="M222.1 65.4l.2 .2M222.3 65.4l-.2 .2M223.2 74.4l.2 .2M223.4 74.4l-.2 .2M77.9 81.2l.2-.2 .3 .2-.3 .3zM77.9 82.6l.2-.3 .3 .3-.3 .2zM80.7 88.7l.2 .2M80.7 89.3l.2 .2M80.7 93.8l.2 .2M80.7 94.5l.2 .2M80.9 88.7l-.2 .2M80.9 89.3l-.2 .2"/>
<path d="M80.9 93.8l-.2 .2M80.9 94.5l-.2 .2M86.8 88.1l.2 .2M86.8 92.9l.2 .2M87 88.1l-.2 .2M87 92.9l-.2 .2M88.3 86.8l.2 .2M88.5 86.8l-.2 .2M95.5 86.8l.2 .2M95.7 86.8l-.2 .2M97.7 92.9l.2 .2M97.7 87.8l.2 .3"/>
<path d="M97.9 92.9l-.2 .2M97.9 87.8l-.2 .3M98.4 80.3l.2 .2M98.6 80.3l-.2 .2M101.5 83.5l.2 .2M101.7 83.5l-.2 .2M102.5 80.3l.2 .2M102.7 80.3l-.2 .2M104.9 80.3l.2 .2M105.1 80.3l-.2 .2M106.7 90.2l.2 .2M106.7 92.9l.2 .2"/>
<path d="M106.9 90.2l-.2 .2M106.9 92.9l-.2 .2M107 86.9l.6 .6M107 88.6l.6 .6M107.3 86.9l.3 .3-.3 .3-.3-.3zM107.3 88.6l.3 .3-.3 .3-.3-.3zM107.6 86.9l-.6 .6M107.6 88.6l-.6 .6M108.7 88.6l.6 .6M108.7 86.9l.6 .6M109 86.9l.3 .3-.3 .3-.3-.3zM109 88.6l.3 .3-.3 .3-.3-.3z"/>
<path d="M109.3 88.6l-.6 .6M109.3 86.9l-.6 .6M110.4 88.6l.6 .6M110.4 86.9l.6 .6M110.7 86.9l.3 .3-.3 .3-.3-.3zM110.7 88.6l.3 .3-.3 .3-.3-.3zM111 86.9l-.6 .6M111 88.6l-.6 .6M111.9 84.3l.2 .2M112.1 88.6l.7 .6M112.1 86.9l.7 .6M112.1 84.3l-.2 .2"/>
<path d="M112.4 86.9l.4 .3-.4 .3-.3-.3zM112.4 88.6l.4 .3-.4 .3-.3-.3zM112.8 86.9l-.7 .6M112.8 88.6l-.7 .6M113.2 82.2l.2 .2M113.4 82.2l-.2 .2M113.8 87.2l.3-.3 .4 .3-.4 .3zM113.8 88.9l.3-.3 .4 .3-.4 .3zM113.8 88.6l.7 .6M113.8 86.9l.7 .6M114.5 86.9l-.7 .6M114.5 88.6l-.7 .6"/>
<path d="M115.5 87.2l.3-.3 .4 .3-.4 .3zM115.5 88.9l.3-.3 .4 .3-.4 .3zM115.5 88.6l.7 .6M115.5 86.9l.7 .6M116.2 86.9l-.7 .6M116.2 88.6l-.7 .6M117.2 87.2l.4-.3 .3 .3-.3 .3zM117.2 88.6l.7 .6M117.2 86.9l.7 .6M117.6 88.6l.3 .3-.3 .3-.4-.3zM117.9 86.9l-.7 .6M117.9 88.6l-.7 .6"/>
<path d="M118.9 87.2l.4-.3 .3 .3-.3 .3zM118.9 88.6l.7 .6M118.9 86.9l.7 .6M119.3 88.6l.3 .3-.3 .3-.4-.3zM119.6 88.6l-.7 .6M119.6 86.9l-.7 .6M123.9 80.7l.2 .2M124.1 80.7l-.2 .2M127.5 82l.2 .2M127.7 82l-.2 .2M130.8 81.2l.2 .2M130.8 83.8l.2 .2"/>
<path d="M131 81.2l-.2 .2M131 83.8l-.2 .2M133.1 80.4l.2 .2M133.3 80.4l-.2 .2M133.3 81.2l.2 .2M133.3 83.8l.2 .2M133.5 81.2l-.2 .2M133.5 83.8l-.2 .2M156.1 80.4l.2 .2M156.3 80.4l-.2 .2M162.5 80.2l.2 .2M162.7 80.2l-.2 .2"/>
<path d="M177.6 80.2l.2 .2M177.8 80.2l-.2 .2M190.8 99l.6 .6M190.9 99h.4v.5h-.4zM191.4 99l-.6 .6M192.5 99l.6 .6M192.6 99h.4v.5h-.4zM192.8 80.2l.2 .2M193 80.2l-.2 .2M193.1 99l-.6 .6M194.2 99l.6 .6M194.3 99h.4v.5h-.4z"/>
<path d="M194.8 99l-.6 .6M195.8 99l.7 .6M195.9 99h.5v.5h-.5zM196.5 99l-.7 .6M197.5 99l.7 .6M197.6 99h.5v.5h-.5zM198.2 99l-.7 .6M199.2 99l.7 .6M199.3 99h.5v.5h-.5zM199.9 99l-.7 .6M200.9 99l.6 .6M201 99h.4v.5h-.4z"/>
<path d="M201.5 99l-.6 .6M202.6 99l.6 .6M202.7 99h.4v.5h-.4zM203.2 99l-.6 .6M208 80.2l.2 .2M208.2 80.2l-.2 .2M213.6 89.7l.2 .2M213.8 89.7l-.2 .2M218.7 93.6h.2M218.8 93.5v.3M219.3 92.6l.2 .2M219.5 92.6l-.2 .2"/>
<path d="M220.4 97.8h.2M220.4 89.9l.2 .2M220.5 97.7v.2M220.6 89.9l-.2 .2M221.2 83.8l.2 .2M221.4 83.8l-.2 .2M221.5 89.6l.2 .2M221.7 89.6l-.2 .2M223 82.9l.2 .2M223.2 82.9l-.2 .2M223.4 86.8l.2 .2M223.6 86.8l-.2 .2"/>
<path d="M224 83.8l.2 .2M224.2 83.8l-.2 .2M77.9 101l.2-.3 .3 .3-.3 .2zM77.9 102.3l.2-.2 .3 .2-.3 .3zM77.9 103.7l.2-.3 .3 .3-.3 .2zM77.9 105l.2-.2 .3 .2-.3 .3zM77.9 106.4l.2-.3 .3 .3-.3 .2zM77.9 107.7l.2-.2 .3 .2-.3 .3zM77.9 109.1l.2-.3 .3 .3-.3 .2zM214 106.7l.2 .2M214.2 106.7l-.2 .2M215.7 107.9l.2 .2"/>
<path d="M215.9 107.9l-.2 .2M219.1 103.7l.2 .2M219.3 103.7l-.2 .2M220.4 103.8h.2M220.4 106.7l.2 .2M220.4 109.8l.2 .2M220.5 103.6v.3M220.6 106.7l-.2 .2M220.6 109.8l-.2 .2M221.3 103.7l.2 .2M221.5 103.7l-.2 .2M226 102.8l.2 .2"/>
<path d="M226.2 102.8l-.2 .2M69.1 139.5l.3-.3 .4 .3-.4 .4zM69.1 139.2l.7 .7M69.1 137.4l.7 .7M69.2 135.7l.6 .6M69.2 136h.6M69.2 137.5h.5v.5h-.5zM69.2 133.9l.6 .6M69.3 132.4l.2-.2 .3 .2-.3 .3zM69.4 130.5h.3v.3h-.3zM69.5 135.7v.6M69.5 128.9h.3"/>
<path d="M69.6 125.2l.2 .2M69.6 128.7v.3M69.8 133.9l-.6 .6M69.8 125.2l-.2 .2M69.8 135.7l-.6 .6M69.8 137.4l-.7 .7M69.8 139.2l-.7 .7M75.1 121.8v1.1l.2 .2M79.3 125l.4 .2M79.3 126.8l.4 .2M79.3 128.6l.4 .2M79.3 130.4l.4 .2"/>
<path d="M79.3 132.1l.4 .2M79.3 133.9l.4 .2M79.3 135.7l.4 .2M79.3 137.5l.4 .2M79.3 139.3l.4 .1M79.7 125.2l.2-.2 .3 .1 .1 .8M79.7 125.2v.7M79.7 127v.7M79.7 128.8v.7M79.7 130.6v.7M79.7 132.3v.7M79.7 134.1v.7"/>
<path d="M79.7 135.9v.7M79.7 137.7v.7M79.7 139.4v.8M79.7 127l.2-.2 .3 .1 .1 .8M79.7 128.8l.2-.2 .3 .1 .1 .8M79.7 130.6l.2-.2h.3l.1 .9M79.7 132.3l.2-.2 .3 .1 .1 .8M79.7 134.1l.2-.2 .3 .1 .1 .8M79.7 135.9l.2-.2 .3 .1 .1 .8M79.7 137.7l.2-.2h.3l.1 .9M79.7 139.4l.2-.1h.3l.1 .9M82.9 124.5l-1.2 1.8"/>
<path d="M82.9 126.3l-1.2 1.7M82.9 128.1l-1.2 1.7M82.9 129.9l-1.2 1.7M82.9 131.6l-1.2 1.8M82.9 133.4l-1.2 1.7M82.9 135.2l-1.2 1.7M82.9 137l-1.2 1.7M82.9 138.7l-1.2 1.8M91.4 124.6v.2M91.4 126.4v.2M91.4 128.1v.3M91.4 129.9v.3"/>
<path d="M91.4 131.7v.3M91.4 133.5v.2M91.4 135.3v.2M91.4 137v.3M91.4 138.8v.3M91.9 124.6v.2M91.9 126.4v.2M91.9 128.1v.3M91.9 129.9v.3M91.9 131.7v.3M91.9 133.5v.2M91.9 135.3v.2"/>
<path d="M91.9 137v.3M91.9 138.8v.3M68.4 153.4l1.4 1.3M68.4 154h1.4M68.6 151.1h1v.9h-1zM68.7 149.4h1.1M68.8 147.2h1M68.8 145.2l.5-.5 .5 .5-.5 .4zM68.9 146.9h.7v.7h-.7zM69 141.3h.8M69.1 142.9h.6v.6h-.6zM69.1 150.9l.7 .7-.7 .6-.7-.6z"/>
<path d="M69.1 153.4v1.3M69.3 148.9l.5 .5-.5 .5-.6-.5zM69.3 148.9v1M69.3 146.7v1M69.4 141v.7M69.8 153.4l-1.4 1.3M79.3 141.1l.4 .2M79.3 142.9l.4 .2M79.3 144.9l.4 .2M79.3 147l.4 .2M79.3 149.1l.4 .2M79.3 151.3l.4 .2"/>
<path d="M79.3 153.8l.4 .2M79.7 141.3v.7M79.7 143.1v.7M79.7 145.1v.7M79.7 147.2v.7M79.7 149.3v.7M79.7 151.5v.7M79.7 154v.7M79.7 141.3l.2-.2h.3l.1 .9M79.7 143.1l.2-.2 .3 .1 .1 .8M79.7 145.1l.2-.2h.3l.1 .9M79.7 147.2l.2-.2h.3l.1 .9"/>
<path d="M79.7 149.3l.2-.2 .3 .1 .1 .8M79.7 151.5l.2-.2h.3l.1 .9M79.7 154l.2-.2h.3l.1 .9M82.9 140.6l-1.2 1.7M82.9 142.4l-1.2 1.8M82.9 144.4l-1.2 1.7M82.9 146.4l-1.2 1.8M82.9 148.6l-1.2 1.7M82.9 150.8l-1.2 1.7M82.9 153.3l-1.2 1.7M91.4 140.6v.3M91.4 142.5v.2"/>
<path d="M91.4 144.4v.3M91.4 146.5v.3M91.4 148.7v.2M91.4 150.8v.3M91.4 153.3v.3M91.9 140.6v.3M91.9 142.5v.2M91.9 144.4v.3M91.9 146.5v.3M91.9 148.7v.2M91.9 150.8v.3M91.9 153.3v.3"/>
<circle cx="122.2" cy="15.8" r=".47"/>
<circle cx="122.2" cy="11.6" r=".47"/>
<circle cx="122.2" cy="7.3" r=".47"/>
<circle cx="133" cy="15.8" r=".47"/>
<circle cx="133" cy="11.6" r=".47"/>
<circle cx="133" cy="7.3" r=".47"/>
<circle cx="166" cy="10.4" r=".4"/>
<circle cx="166" cy="7.1" r=".4"/>
<circle cx="169.4" cy="10.4" r=".4"/>
<circle cx="169.4" cy="7.1" r=".4"/>
<circle cx="172.7" cy="10.4" r=".4"/>
<circle cx="172.7" cy="7.1" r=".4"/>
<circle cx="184.9" cy="15.8" r=".47"/>
<circle cx="184.9" cy="7.3" r=".47"/>
<circle cx="184.9" cy="11.6" r=".47"/>
<circle cx="195.7" cy="15.8" r=".47"/>
<circle cx="195.7" cy="7.3" r=".47"/>
<circle cx="195.7" cy="11.6" r=".47"/>
<circle cx="205.8" cy="15.8" r=".47"/>
<circle cx="205.8" cy="7.3" r=".47"/>
<circle cx="205.8" cy="11.6" r=".47"/>
<circle cx="216.5" cy="15.8" r=".47"/>
<circle cx="216.5" cy="7.3" r=".47"/>
<circle cx="216.5" cy="11.6" r=".47"/>
<circle cx="82.5" cy="56.4" r=".37"/>
<circle cx="85.5" cy="56.4" r=".37"/>
<circle cx="114.4" cy="41.9" r=".27"/>
<circle cx="114.4" cy="47" r=".27"/>
<circle cx="116.1" cy="47" r=".27"/>
<circle cx="116.1" cy="41.9" r=".27"/>
<circle cx="117.8" cy="47" r=".27"/>
<circle cx="117.8" cy="41.9" r=".27"/>
<circle cx="119.5" cy="41.9" r=".27"/>
<circle cx="119.5" cy="47" r=".27"/>
<circle cx="130.8" cy="50.5" r=".1"/>
<circle cx="130.8" cy="51.8" r=".1"/>
<circle cx="130.8" cy="51.2" r=".1"/>
<circle cx="131.5" cy="51.8" r=".1"/>
<circle cx="131.5" cy="50.5" r=".1"/>
<circle cx="131.5" cy="51.2" r=".1"/>
<circle cx="132.2" cy="51.8" r=".1"/>
<circle cx="132.2" cy="50.5" r=".1"/>
<circle cx="132.2" cy="51.2" r=".1"/>
<circle cx="82.5" cy="60.7" r=".37"/>
<circle cx="85.5" cy="60.7" r=".37"/>
<circle cx="69.5" cy="134.2" r=".27"/>
<circle cx="69.7" cy="127.1" r=".1"/>
<circle cx="69.1" cy="154" r=".67"/>
<circle cx="69.3" cy="145.2" r=".47"/>
<circle cx="69.4" cy="143.2" r=".4"/>
<circle cx="69.4" cy="141.3" r=".37"/>
</g>
<g fill="none" stroke="#000" stroke-width=".27">
<path d="M72.3 12.8l2.7 2.7M72.3 14.2h2.7M73.6 12.8v2.7M75 12.8l-2.7 2.7M222 14.2h2.7M222 12.8l2.7 2.7M223.4 12.8v2.7M224.7 12.8l-2.7 2.7M72.3 115.8l2.7 2.7M72.3 117.1h2.7M73.6 115.8v2.7M75 115.8l-2.7 2.7"/>
<path d="M222 117.1h2.7M222 115.8l2.7 2.7M223.4 115.8v2.7M224.7 115.8l-2.7 2.7"/>
<circle cx="73.6" cy="14.2" r="1.35"/>
<circle cx="223.4" cy="14.2" r="1.35"/>
<circle cx="73.6" cy="117.1" r="1.35"/>
<circle cx="223.4" cy="117.1" r="1.35"/>
</g>
<use href="#words"/>
</svg>
